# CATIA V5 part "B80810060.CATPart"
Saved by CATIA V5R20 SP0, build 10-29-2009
Part number: B80810060
Revision: 2
Definition: design
Nomenclature: B80810060
Source: made
Description: NOT SPECIFIED
Bounding box of the stored display mesh (mm): x -6.824 to 6.824, y -7 to 7, z 0 to 60
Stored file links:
  C:\Users\Raffaele\Desktop\3D X SITO CF\BOLEX\4-PILLAR REF 808\B80810060.CATPart

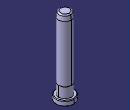
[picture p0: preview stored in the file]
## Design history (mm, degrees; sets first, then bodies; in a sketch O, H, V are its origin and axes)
Body1 "MANIFOLD_SOLID_BREP #450" (main body)
  Solid1: solid without history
